VERSION 5.7 ;
BUSBITCHARS "[]" ;
DIVIDERCHAR "/" ;
UNITS
  DATABASE MICRONS 1000 ;
END UNITS

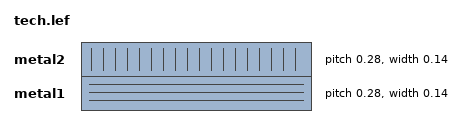
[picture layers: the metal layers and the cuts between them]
LAYER metal1
  TYPE ROUTING ;
  DIRECTION HORIZONTAL ;
  WIDTH 0.14 ;
  PITCH 0.28 ;
END metal1

LAYER metal2
  TYPE ROUTING ;
  DIRECTION VERTICAL ;
  WIDTH 0.14 ;
  PITCH 0.28 ;
END metal2

SITE core
  CLASS CORE ;
  SIZE 0.46 BY 1.4 ;
END core

END LIBRARY
